VERSION 5.8 ;
BUSBITCHARS "[]" ;
DIVIDERCHAR "/" ;
UNITS
    DATABASE MICRONS 1000 ;
END UNITS

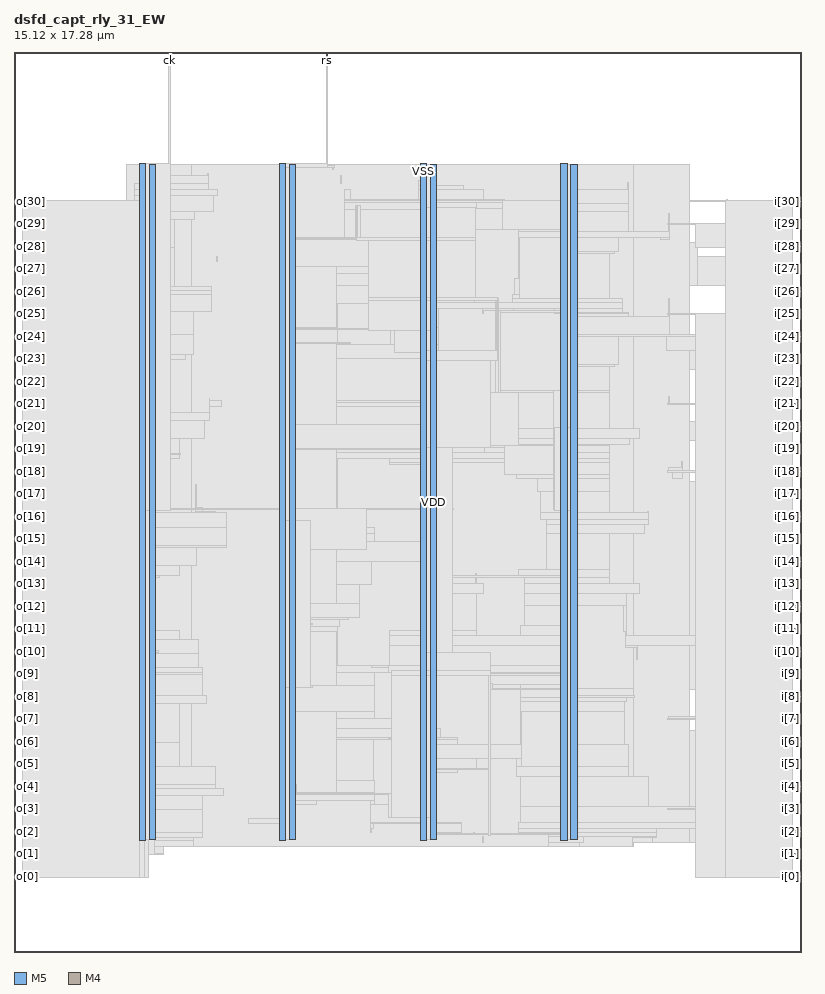
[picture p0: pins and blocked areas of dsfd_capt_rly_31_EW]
MACRO dsfd_capt_rly_31_EW
  FOREIGN dsfd_capt_rly_31_EW 0 0 ;
  CLASS BLOCK ;
  SIZE 15.12 BY 17.28 ;
  PIN ck
    DIRECTION INPUT ;
    USE SIGNAL ;
    PORT
      LAYER M5 ;
        RECT  2.976 17.088 3 17.28 ;
    END
  END ck
  PIN i[0]
    DIRECTION INPUT ;
    USE SIGNAL ;
    PORT
      LAYER M4 ;
        RECT  14.928 1.44 15.12 1.464 ;
    END
  END i[0]
  PIN i[10]
    DIRECTION INPUT ;
    USE SIGNAL ;
    PORT
      LAYER M4 ;
        RECT  14.928 5.76 15.12 5.784 ;
    END
  END i[10]
  PIN i[11]
    DIRECTION INPUT ;
    USE SIGNAL ;
    PORT
      LAYER M4 ;
        RECT  14.928 6.192 15.12 6.216 ;
    END
  END i[11]
  PIN i[12]
    DIRECTION INPUT ;
    USE SIGNAL ;
    PORT
      LAYER M4 ;
        RECT  14.928 6.624 15.12 6.648 ;
    END
  END i[12]
  PIN i[13]
    DIRECTION INPUT ;
    USE SIGNAL ;
    PORT
      LAYER M4 ;
        RECT  14.928 7.056 15.12 7.08 ;
    END
  END i[13]
  PIN i[14]
    DIRECTION INPUT ;
    USE SIGNAL ;
    PORT
      LAYER M4 ;
        RECT  14.928 7.488 15.12 7.512 ;
    END
  END i[14]
  PIN i[15]
    DIRECTION INPUT ;
    USE SIGNAL ;
    PORT
      LAYER M4 ;
        RECT  14.928 7.92 15.12 7.944 ;
    END
  END i[15]
  PIN i[16]
    DIRECTION INPUT ;
    USE SIGNAL ;
    PORT
      LAYER M4 ;
        RECT  14.928 8.352 15.12 8.376 ;
    END
  END i[16]
  PIN i[17]
    DIRECTION INPUT ;
    USE SIGNAL ;
    PORT
      LAYER M4 ;
        RECT  14.928 8.784 15.12 8.808 ;
    END
  END i[17]
  PIN i[18]
    DIRECTION INPUT ;
    USE SIGNAL ;
    PORT
      LAYER M4 ;
        RECT  14.928 9.216 15.12 9.24 ;
    END
  END i[18]
  PIN i[19]
    DIRECTION INPUT ;
    USE SIGNAL ;
    PORT
      LAYER M4 ;
        RECT  14.928 9.648 15.12 9.672 ;
    END
  END i[19]
  PIN i[1]
    DIRECTION INPUT ;
    USE SIGNAL ;
    PORT
      LAYER M4 ;
        RECT  14.928 1.872 15.12 1.896 ;
    END
  END i[1]
  PIN i[20]
    DIRECTION INPUT ;
    USE SIGNAL ;
    PORT
      LAYER M4 ;
        RECT  14.928 10.08 15.12 10.104 ;
    END
  END i[20]
  PIN i[21]
    DIRECTION INPUT ;
    USE SIGNAL ;
    PORT
      LAYER M4 ;
        RECT  14.928 10.512 15.12 10.536 ;
    END
  END i[21]
  PIN i[22]
    DIRECTION INPUT ;
    USE SIGNAL ;
    PORT
      LAYER M4 ;
        RECT  14.928 10.944 15.12 10.968 ;
    END
  END i[22]
  PIN i[23]
    DIRECTION INPUT ;
    USE SIGNAL ;
    PORT
      LAYER M4 ;
        RECT  14.928 11.376 15.12 11.4 ;
    END
  END i[23]
  PIN i[24]
    DIRECTION INPUT ;
    USE SIGNAL ;
    PORT
      LAYER M4 ;
        RECT  14.928 11.808 15.12 11.832 ;
    END
  END i[24]
  PIN i[25]
    DIRECTION INPUT ;
    USE SIGNAL ;
    PORT
      LAYER M4 ;
        RECT  14.928 12.24 15.12 12.264 ;
    END
  END i[25]
  PIN i[26]
    DIRECTION INPUT ;
    USE SIGNAL ;
    PORT
      LAYER M4 ;
        RECT  14.928 12.672 15.12 12.696 ;
    END
  END i[26]
  PIN i[27]
    DIRECTION INPUT ;
    USE SIGNAL ;
    PORT
      LAYER M4 ;
        RECT  14.928 13.104 15.12 13.128 ;
    END
  END i[27]
  PIN i[28]
    DIRECTION INPUT ;
    USE SIGNAL ;
    PORT
      LAYER M4 ;
        RECT  14.928 13.536 15.12 13.56 ;
    END
  END i[28]
  PIN i[29]
    DIRECTION INPUT ;
    USE SIGNAL ;
    PORT
      LAYER M4 ;
        RECT  14.928 13.968 15.12 13.992 ;
    END
  END i[29]
  PIN i[2]
    DIRECTION INPUT ;
    USE SIGNAL ;
    PORT
      LAYER M4 ;
        RECT  14.928 2.304 15.12 2.328 ;
    END
  END i[2]
  PIN i[30]
    DIRECTION INPUT ;
    USE SIGNAL ;
    PORT
      LAYER M4 ;
        RECT  14.928 14.4 15.12 14.424 ;
    END
  END i[30]
  PIN i[3]
    DIRECTION INPUT ;
    USE SIGNAL ;
    PORT
      LAYER M4 ;
        RECT  14.928 2.736 15.12 2.76 ;
    END
  END i[3]
  PIN i[4]
    DIRECTION INPUT ;
    USE SIGNAL ;
    PORT
      LAYER M4 ;
        RECT  14.928 3.168 15.12 3.192 ;
    END
  END i[4]
  PIN i[5]
    DIRECTION INPUT ;
    USE SIGNAL ;
    PORT
      LAYER M4 ;
        RECT  14.928 3.6 15.12 3.624 ;
    END
  END i[5]
  PIN i[6]
    DIRECTION INPUT ;
    USE SIGNAL ;
    PORT
      LAYER M4 ;
        RECT  14.928 4.032 15.12 4.056 ;
    END
  END i[6]
  PIN i[7]
    DIRECTION INPUT ;
    USE SIGNAL ;
    PORT
      LAYER M4 ;
        RECT  14.928 4.464 15.12 4.488 ;
    END
  END i[7]
  PIN i[8]
    DIRECTION INPUT ;
    USE SIGNAL ;
    PORT
      LAYER M4 ;
        RECT  14.928 4.896 15.12 4.92 ;
    END
  END i[8]
  PIN i[9]
    DIRECTION INPUT ;
    USE SIGNAL ;
    PORT
      LAYER M4 ;
        RECT  14.928 5.328 15.12 5.352 ;
    END
  END i[9]
  PIN o[0]
    DIRECTION OUTPUT ;
    USE SIGNAL ;
    PORT
      LAYER M4 ;
        RECT  0 1.44 0.192 1.464 ;
    END
  END o[0]
  PIN o[10]
    DIRECTION OUTPUT ;
    USE SIGNAL ;
    PORT
      LAYER M4 ;
        RECT  0 5.76 0.192 5.784 ;
    END
  END o[10]
  PIN o[11]
    DIRECTION OUTPUT ;
    USE SIGNAL ;
    PORT
      LAYER M4 ;
        RECT  0 6.192 0.192 6.216 ;
    END
  END o[11]
  PIN o[12]
    DIRECTION OUTPUT ;
    USE SIGNAL ;
    PORT
      LAYER M4 ;
        RECT  0 6.624 0.192 6.648 ;
    END
  END o[12]
  PIN o[13]
    DIRECTION OUTPUT ;
    USE SIGNAL ;
    PORT
      LAYER M4 ;
        RECT  0 7.056 0.192 7.08 ;
    END
  END o[13]
  PIN o[14]
    DIRECTION OUTPUT ;
    USE SIGNAL ;
    PORT
      LAYER M4 ;
        RECT  0 7.488 0.192 7.512 ;
    END
  END o[14]
  PIN o[15]
    DIRECTION OUTPUT ;
    USE SIGNAL ;
    PORT
      LAYER M4 ;
        RECT  0 7.92 0.192 7.944 ;
    END
  END o[15]
  PIN o[16]
    DIRECTION OUTPUT ;
    USE SIGNAL ;
    PORT
      LAYER M4 ;
        RECT  0 8.352 0.192 8.376 ;
    END
  END o[16]
  PIN o[17]
    DIRECTION OUTPUT ;
    USE SIGNAL ;
    PORT
      LAYER M4 ;
        RECT  0 8.784 0.192 8.808 ;
    END
  END o[17]
  PIN o[18]
    DIRECTION OUTPUT ;
    USE SIGNAL ;
    PORT
      LAYER M4 ;
        RECT  0 9.216 0.192 9.24 ;
    END
  END o[18]
  PIN o[19]
    DIRECTION OUTPUT ;
    USE SIGNAL ;
    PORT
      LAYER M4 ;
        RECT  0 9.648 0.192 9.672 ;
    END
  END o[19]
  PIN o[1]
    DIRECTION OUTPUT ;
    USE SIGNAL ;
    PORT
      LAYER M4 ;
        RECT  0 1.872 0.192 1.896 ;
    END
  END o[1]
  PIN o[20]
    DIRECTION OUTPUT ;
    USE SIGNAL ;
    PORT
      LAYER M4 ;
        RECT  0 10.08 0.192 10.104 ;
    END
  END o[20]
  PIN o[21]
    DIRECTION OUTPUT ;
    USE SIGNAL ;
    PORT
      LAYER M4 ;
        RECT  0 10.512 0.192 10.536 ;
    END
  END o[21]
  PIN o[22]
    DIRECTION OUTPUT ;
    USE SIGNAL ;
    PORT
      LAYER M4 ;
        RECT  0 10.944 0.192 10.968 ;
    END
  END o[22]
  PIN o[23]
    DIRECTION OUTPUT ;
    USE SIGNAL ;
    PORT
      LAYER M4 ;
        RECT  0 11.376 0.192 11.4 ;
    END
  END o[23]
  PIN o[24]
    DIRECTION OUTPUT ;
    USE SIGNAL ;
    PORT
      LAYER M4 ;
        RECT  0 11.808 0.192 11.832 ;
    END
  END o[24]
  PIN o[25]
    DIRECTION OUTPUT ;
    USE SIGNAL ;
    PORT
      LAYER M4 ;
        RECT  0 12.24 0.192 12.264 ;
    END
  END o[25]
  PIN o[26]
    DIRECTION OUTPUT ;
    USE SIGNAL ;
    PORT
      LAYER M4 ;
        RECT  0 12.672 0.192 12.696 ;
    END
  END o[26]
  PIN o[27]
    DIRECTION OUTPUT ;
    USE SIGNAL ;
    PORT
      LAYER M4 ;
        RECT  0 13.104 0.192 13.128 ;
    END
  END o[27]
  PIN o[28]
    DIRECTION OUTPUT ;
    USE SIGNAL ;
    PORT
      LAYER M4 ;
        RECT  0 13.536 0.192 13.56 ;
    END
  END o[28]
  PIN o[29]
    DIRECTION OUTPUT ;
    USE SIGNAL ;
    PORT
      LAYER M4 ;
        RECT  0 13.968 0.192 13.992 ;
    END
  END o[29]
  PIN o[2]
    DIRECTION OUTPUT ;
    USE SIGNAL ;
    PORT
      LAYER M4 ;
        RECT  0 2.304 0.192 2.328 ;
    END
  END o[2]
  PIN o[30]
    DIRECTION OUTPUT ;
    USE SIGNAL ;
    PORT
      LAYER M4 ;
        RECT  0 14.4 0.192 14.424 ;
    END
  END o[30]
  PIN o[3]
    DIRECTION OUTPUT ;
    USE SIGNAL ;
    PORT
      LAYER M4 ;
        RECT  0 2.736 0.192 2.76 ;
    END
  END o[3]
  PIN o[4]
    DIRECTION OUTPUT ;
    USE SIGNAL ;
    PORT
      LAYER M4 ;
        RECT  0 3.168 0.192 3.192 ;
    END
  END o[4]
  PIN o[5]
    DIRECTION OUTPUT ;
    USE SIGNAL ;
    PORT
      LAYER M4 ;
        RECT  0 3.6 0.192 3.624 ;
    END
  END o[5]
  PIN o[6]
    DIRECTION OUTPUT ;
    USE SIGNAL ;
    PORT
      LAYER M4 ;
        RECT  0 4.032 0.192 4.056 ;
    END
  END o[6]
  PIN o[7]
    DIRECTION OUTPUT ;
    USE SIGNAL ;
    PORT
      LAYER M4 ;
        RECT  0 4.464 0.192 4.488 ;
    END
  END o[7]
  PIN o[8]
    DIRECTION OUTPUT ;
    USE SIGNAL ;
    PORT
      LAYER M4 ;
        RECT  0 4.896 0.192 4.92 ;
    END
  END o[8]
  PIN o[9]
    DIRECTION OUTPUT ;
    USE SIGNAL ;
    PORT
      LAYER M4 ;
        RECT  0 5.328 0.192 5.352 ;
    END
  END o[9]
  PIN rs
    DIRECTION INPUT ;
    USE SIGNAL ;
    PORT
      LAYER M5 ;
        RECT  6 17.088 6.024 17.28 ;
    END
  END rs
  PIN VDD
    DIRECTION INOUT ;
    USE POWER ;
    PORT
      LAYER M5 ;
        RECT  10.692 2.151 10.812 15.129 ;
        RECT  7.992 2.151 8.112 15.129 ;
        RECT  5.292 2.151 5.412 15.129 ;
        RECT  2.592 2.151 2.712 15.129 ;
    END
  END VDD
  PIN VSS
    DIRECTION INOUT ;
    USE GROUND ;
    PORT
      LAYER M5 ;
        RECT  10.5 2.137 10.62 15.143 ;
        RECT  7.8 2.137 7.92 15.143 ;
        RECT  5.1 2.137 5.22 15.143 ;
        RECT  2.4 2.137 2.52 15.143 ;
    END
  END VSS
  OBS
    LAYER RVTN ;
     RECT  2.16 2.16 12.96 2.295 ;
     RECT  2.16 2.565 12.96 2.835 ;
     RECT  2.16 3.105 12.96 3.375 ;
     RECT  2.16 3.645 12.96 3.915 ;
     RECT  2.16 4.185 12.96 4.455 ;
     RECT  2.16 4.725 12.96 4.995 ;
     RECT  2.16 5.265 12.96 5.535 ;
     RECT  2.16 5.805 12.96 6.075 ;
     RECT  2.16 6.345 12.96 6.615 ;
     RECT  2.16 6.885 12.96 7.155 ;
     RECT  2.16 7.425 12.96 7.695 ;
     RECT  2.16 7.965 12.96 8.235 ;
     RECT  2.16 8.505 12.96 8.775 ;
     RECT  2.16 9.045 12.96 9.315 ;
     RECT  2.16 9.585 12.96 9.855 ;
     RECT  2.16 10.125 12.96 10.395 ;
     RECT  2.16 10.665 12.96 10.935 ;
     RECT  2.16 11.205 12.96 11.475 ;
     RECT  2.16 11.745 12.96 12.015 ;
     RECT  2.16 12.285 12.96 12.555 ;
     RECT  2.16 12.825 12.96 13.095 ;
     RECT  2.16 13.365 12.96 13.635 ;
     RECT  2.16 13.905 12.96 14.175 ;
     RECT  2.16 14.445 12.96 14.715 ;
     RECT  2.16 14.985 12.96 15.12 ;
    LAYER RVTP ;
     RECT  2.16 2.295 12.96 2.565 ;
     RECT  2.16 2.835 12.96 3.105 ;
     RECT  2.16 3.375 12.96 3.645 ;
     RECT  2.16 3.915 12.96 4.185 ;
     RECT  2.16 4.455 12.96 4.725 ;
     RECT  2.16 4.995 12.96 5.265 ;
     RECT  2.16 5.535 12.96 5.805 ;
     RECT  2.16 6.075 12.96 6.345 ;
     RECT  2.16 6.615 12.96 6.885 ;
     RECT  2.16 7.155 12.96 7.425 ;
     RECT  2.16 7.695 12.96 7.965 ;
     RECT  2.16 8.235 12.96 8.505 ;
     RECT  2.16 8.775 12.96 9.045 ;
     RECT  2.16 9.315 12.96 9.585 ;
     RECT  2.16 9.855 12.96 10.125 ;
     RECT  2.16 10.395 12.96 10.665 ;
     RECT  2.16 10.935 12.96 11.205 ;
     RECT  2.16 11.475 12.96 11.745 ;
     RECT  2.16 12.015 12.96 12.285 ;
     RECT  2.16 12.555 12.96 12.825 ;
     RECT  2.16 13.095 12.96 13.365 ;
     RECT  2.16 13.635 12.96 13.905 ;
     RECT  2.16 14.175 12.96 14.445 ;
     RECT  2.16 14.715 12.96 14.985 ;
    LAYER M1 ;
     RECT  2.16 2.151 12.96 15.129 ;
    LAYER M2 ;
     RECT  2.16 2.151 3.415 15.129 ;
     RECT  3.415 2.034 11.903 15.129 ;
     RECT  11.903 2.106 12.96 15.129 ;
     RECT  12.96 2.106 13.127 4.248 ;
     RECT  12.96 5.04 13.127 9.036 ;
     RECT  12.96 9.828 13.127 10.188 ;
     RECT  12.96 11.178 13.127 11.844 ;
     RECT  12.96 12.798 13.127 13.626 ;
     RECT  13.127 2.268 13.703 2.286 ;
     RECT  13.127 6.822 13.703 6.84 ;
     RECT  13.127 9.018 13.703 9.036 ;
     RECT  13.127 12.798 13.703 13.356 ;
     RECT  12.96 14.418 13.703 14.436 ;
     RECT  13.127 11.178 14.279 11.196 ;
     RECT  13.703 13.338 14.279 13.356 ;
    LAYER M3 ;
     RECT  2.556 1.435 2.574 1.867 ;
     RECT  13.104 1.435 13.122 1.867 ;
     RECT  2.556 1.867 2.862 2.029 ;
     RECT  10.26 2.029 10.854 2.101 ;
     RECT  11.88 2.029 11.898 2.101 ;
     RECT  2.556 2.029 3.438 2.143 ;
     RECT  2.415 2.143 3.438 2.191 ;
     RECT  11.88 2.101 12.258 2.191 ;
     RECT  9 2.101 9.018 2.219 ;
     RECT  10.26 2.101 10.926 2.227 ;
     RECT  11.88 2.191 12.33 2.227 ;
     RECT  8.82 2.251 8.838 2.291 ;
     RECT  13.104 1.867 13.698 2.291 ;
     RECT  2.415 2.191 3.618 2.299 ;
     RECT  7.815 2.143 7.905 2.299 ;
     RECT  10.26 2.227 12.33 2.299 ;
     RECT  6.84 2.299 6.858 2.371 ;
     RECT  9.684 2.299 12.33 2.371 ;
     RECT  13.104 2.291 13.122 2.371 ;
     RECT  5.115 2.143 5.205 2.413 ;
     RECT  5.115 2.413 5.397 2.461 ;
     RECT  6.84 2.371 6.894 2.461 ;
     RECT  7.815 2.299 8.586 2.461 ;
     RECT  6.84 2.461 8.586 2.489 ;
     RECT  9.684 2.371 13.122 2.489 ;
     RECT  4.5 2.461 5.397 2.561 ;
     RECT  2.304 2.299 3.618 2.731 ;
     RECT  9.72 2.489 13.122 2.795 ;
     RECT  6.84 2.489 8.097 2.831 ;
     RECT  5.115 2.561 5.397 2.839 ;
     RECT  5.115 2.839 5.814 2.911 ;
     RECT  6.84 2.831 6.93 2.911 ;
     RECT  2.268 2.731 3.618 3.001 ;
     RECT  5.115 2.911 6.93 3.065 ;
     RECT  2.268 3.001 4.014 3.137 ;
     RECT  2.268 3.137 3.87 3.209 ;
     RECT  5.115 3.065 5.418 3.209 ;
     RECT  6.192 3.065 6.93 3.299 ;
     RECT  9.72 2.795 12.186 3.371 ;
     RECT  9.72 3.371 11.79 3.379 ;
     RECT  7.815 2.831 8.097 3.451 ;
     RECT  7.815 3.451 8.514 3.499 ;
     RECT  2.415 3.209 3.87 3.569 ;
     RECT  9.648 3.379 11.79 3.569 ;
     RECT  7.815 3.499 8.874 3.721 ;
     RECT  9.648 3.569 9.738 3.721 ;
     RECT  7.815 3.721 9.738 3.983 ;
     RECT  10.515 3.569 11.79 3.983 ;
     RECT  2.415 3.569 3.186 4.027 ;
     RECT  6.192 3.299 6.894 4.075 ;
     RECT  7.815 3.983 8.514 4.075 ;
     RECT  6.192 4.075 8.514 4.109 ;
     RECT  6.192 4.109 8.19 4.289 ;
     RECT  13.104 2.795 13.122 4.459 ;
     RECT  6.192 4.289 8.097 4.487 ;
     RECT  12.564 4.459 13.122 4.523 ;
     RECT  5.115 3.209 5.397 4.621 ;
     RECT  6.192 4.487 6.93 4.621 ;
     RECT  9.72 3.983 9.738 4.621 ;
     RECT  10.515 3.983 11.718 4.621 ;
     RECT  2.304 4.027 3.186 4.765 ;
     RECT  9.72 4.621 11.718 4.801 ;
     RECT  9.72 4.801 11.754 4.891 ;
     RECT  2.304 4.765 3.69 4.919 ;
     RECT  9.72 4.891 11.898 5.063 ;
     RECT  5.115 4.621 6.93 5.117 ;
     RECT  9.72 5.063 10.797 5.131 ;
     RECT  9.144 5.131 10.797 5.305 ;
     RECT  2.304 4.919 3.618 5.323 ;
     RECT  7.815 4.487 8.097 5.341 ;
     RECT  8.82 5.305 10.797 5.341 ;
     RECT  2.268 5.323 3.618 5.369 ;
     RECT  6.192 5.117 6.93 5.371 ;
     RECT  7.815 5.341 10.797 5.371 ;
     RECT  2.376 5.369 3.618 5.459 ;
     RECT  6.192 5.371 10.797 5.501 ;
     RECT  2.376 5.459 3.546 5.729 ;
     RECT  11.952 5.611 11.97 5.845 ;
     RECT  7.2 5.501 10.797 5.881 ;
     RECT  11.736 5.845 11.97 5.881 ;
     RECT  13.104 4.523 13.122 5.881 ;
     RECT  2.412 5.729 3.546 5.999 ;
     RECT  7.2 5.881 10.818 6.071 ;
     RECT  11.736 5.881 13.122 6.071 ;
     RECT  5.115 5.117 5.397 6.151 ;
     RECT  6.192 5.501 6.21 6.151 ;
     RECT  11.736 6.071 11.754 6.151 ;
     RECT  2.412 5.999 3.186 6.179 ;
     RECT  7.2 6.071 8.874 6.179 ;
     RECT  5.115 6.151 6.21 6.241 ;
     RECT  9.72 6.071 10.818 6.269 ;
     RECT  5.115 6.241 6.246 6.385 ;
     RECT  5.115 6.385 6.426 6.421 ;
     RECT  13.104 6.071 13.122 6.619 ;
     RECT  9.792 6.269 10.818 6.655 ;
     RECT  11.7 6.151 11.754 6.655 ;
     RECT  5.115 6.421 6.642 6.683 ;
     RECT  13.104 6.619 13.698 6.845 ;
     RECT  7.815 6.179 8.874 6.889 ;
     RECT  9.792 6.655 11.754 6.889 ;
     RECT  2.412 6.179 2.697 7.051 ;
     RECT  6.192 6.683 6.642 7.051 ;
     RECT  7.815 6.889 9.018 7.079 ;
     RECT  9.792 6.889 12.006 7.079 ;
     RECT  2.304 7.051 2.697 7.195 ;
     RECT  9.792 7.079 11.43 7.195 ;
     RECT  2.304 7.195 2.79 7.231 ;
     RECT  8.856 7.079 8.874 7.259 ;
     RECT  9.684 7.195 11.43 7.349 ;
     RECT  2.304 7.231 3.186 7.429 ;
     RECT  6.192 7.051 6.858 7.501 ;
     RECT  7.815 7.079 8.097 7.501 ;
     RECT  2.304 7.429 3.51 7.771 ;
     RECT  2.304 7.771 4.086 7.799 ;
     RECT  6.192 7.501 8.097 7.889 ;
     RECT  5.115 6.683 5.397 8.041 ;
     RECT  6.192 7.889 6.93 8.041 ;
     RECT  10.224 7.349 11.43 8.041 ;
     RECT  2.376 7.799 4.086 8.159 ;
     RECT  5.115 8.041 6.93 8.159 ;
     RECT  10.224 8.041 12.114 8.203 ;
     RECT  5.115 8.159 6.462 8.303 ;
     RECT  10.224 8.203 12.186 8.311 ;
     RECT  2.412 8.159 4.086 8.429 ;
     RECT  10.116 8.311 12.186 8.429 ;
     RECT  3.492 8.429 3.87 8.465 ;
     RECT  12.168 8.429 12.186 8.465 ;
     RECT  7.815 7.889 8.097 8.491 ;
     RECT  13.104 6.845 13.122 8.501 ;
     RECT  3.492 8.465 3.618 8.537 ;
     RECT  7.815 8.491 8.406 8.537 ;
     RECT  10.116 8.429 11.43 8.851 ;
     RECT  3.492 8.537 3.51 8.969 ;
     RECT  13.68 8.779 13.698 9.041 ;
     RECT  10.044 8.851 11.43 9.085 ;
     RECT  9.648 9.085 11.43 9.163 ;
     RECT  2.412 8.429 2.697 9.211 ;
     RECT  12.636 9.085 12.834 9.211 ;
     RECT  12.564 9.211 12.834 9.311 ;
     RECT  7.815 8.537 8.097 9.319 ;
     RECT  7.815 9.319 8.19 9.355 ;
     RECT  7.2 9.355 8.19 9.391 ;
     RECT  9.432 9.163 11.43 9.391 ;
     RECT  12.816 9.311 12.834 9.419 ;
     RECT  2.304 9.211 2.697 9.481 ;
     RECT  6.192 8.303 6.21 9.481 ;
     RECT  7.2 9.391 11.43 9.481 ;
     RECT  6.192 9.481 11.43 9.581 ;
     RECT  5.115 8.303 5.397 9.643 ;
     RECT  6.192 9.581 8.097 9.643 ;
     RECT  0.216 9.547 0.234 9.677 ;
     RECT  9.036 9.581 11.43 9.725 ;
     RECT  9.684 9.725 11.43 9.751 ;
     RECT  2.304 9.481 3.186 9.859 ;
     RECT  9.684 9.751 11.826 9.859 ;
     RECT  9.684 9.859 12.006 10.049 ;
     RECT  5.115 9.643 8.097 10.121 ;
     RECT  13.104 9.643 13.122 10.193 ;
     RECT  2.304 9.859 3.654 10.201 ;
     RECT  2.304 10.201 3.762 10.355 ;
     RECT  3.744 10.355 3.762 10.471 ;
     RECT  6.192 10.121 8.097 10.471 ;
     RECT  6.192 10.471 8.478 10.555 ;
     RECT  3.744 10.471 3.978 10.589 ;
     RECT  6.192 10.555 8.874 10.595 ;
     RECT  2.304 10.355 2.79 10.625 ;
     RECT  3.744 10.589 3.762 10.625 ;
     RECT  12.564 10.507 12.582 10.661 ;
     RECT  9.684 10.049 11.43 10.741 ;
     RECT  9.432 10.741 11.43 10.781 ;
     RECT  14.256 10.939 14.274 11.201 ;
     RECT  10.515 10.781 11.43 11.245 ;
     RECT  10.515 11.245 11.538 11.281 ;
     RECT  2.304 10.625 2.697 11.371 ;
     RECT  6.192 10.595 8.514 11.399 ;
     RECT  9.288 11.365 9.306 11.405 ;
     RECT  2.304 11.371 3.294 11.479 ;
     RECT  9.144 11.509 9.162 11.549 ;
     RECT  13.104 11.371 13.122 11.551 ;
     RECT  6.192 11.399 8.154 11.669 ;
     RECT  5.115 10.121 5.397 11.677 ;
     RECT  6.192 11.669 6.462 11.677 ;
     RECT  5.115 11.677 6.462 11.705 ;
     RECT  10.515 11.281 11.61 11.821 ;
     RECT  12.528 11.551 13.122 11.821 ;
     RECT  2.304 11.479 3.438 11.849 ;
     RECT  10.515 11.821 13.122 11.849 ;
     RECT  5.115 11.705 6.21 11.981 ;
     RECT  7.236 11.669 8.154 11.981 ;
     RECT  10.515 11.849 12.582 12.209 ;
     RECT  10.515 12.209 11.79 12.253 ;
     RECT  10.368 12.253 11.79 12.281 ;
     RECT  2.415 11.849 3.438 12.289 ;
     RECT  9 12.253 9.018 12.325 ;
     RECT  7.776 11.981 8.154 12.361 ;
     RECT  9 12.325 9.594 12.361 ;
     RECT  10.368 12.281 11.682 12.361 ;
     RECT  6.192 11.981 6.21 12.451 ;
     RECT  7.776 12.361 11.682 12.479 ;
     RECT  9.576 12.479 11.682 12.551 ;
     RECT  12.564 12.209 12.582 12.551 ;
     RECT  7.776 12.479 8.838 12.557 ;
     RECT  9.576 12.551 9.702 12.623 ;
     RECT  2.415 12.289 3.798 12.631 ;
     RECT  2.304 12.631 3.798 12.701 ;
     RECT  2.412 12.701 3.798 12.785 ;
     RECT  6.192 12.451 6.858 12.793 ;
     RECT  7.776 12.557 8.514 12.793 ;
     RECT  13.68 12.667 13.698 12.821 ;
     RECT  9.612 12.623 9.702 12.929 ;
     RECT  6.192 12.793 8.514 13.019 ;
     RECT  5.115 11.981 5.397 13.171 ;
     RECT  6.192 13.019 8.154 13.171 ;
     RECT  3.888 13.261 3.906 13.361 ;
     RECT  14.256 13.099 14.274 13.361 ;
     RECT  10.515 12.551 11.43 13.405 ;
     RECT  10.515 13.405 11.538 13.441 ;
     RECT  2.412 12.785 3.078 13.531 ;
     RECT  13.104 13.531 13.122 13.631 ;
     RECT  5.115 13.171 8.154 13.709 ;
     RECT  9.684 12.929 9.702 13.711 ;
     RECT  10.515 13.441 11.61 13.711 ;
     RECT  12.42 13.675 12.582 13.711 ;
     RECT  9.684 13.711 12.582 13.829 ;
     RECT  2.304 13.531 3.078 14.071 ;
     RECT  12.564 13.829 12.582 14.171 ;
     RECT  2.304 14.071 3.474 14.215 ;
     RECT  9.684 13.829 11.79 14.215 ;
     RECT  6.336 13.709 8.154 14.251 ;
     RECT  9.648 14.215 11.79 14.369 ;
     RECT  6.336 14.251 8.874 14.395 ;
     RECT  9.648 14.369 9.702 14.395 ;
     RECT  6.336 14.395 9.702 14.429 ;
     RECT  6.336 14.429 9.414 14.441 ;
     RECT  13.68 14.395 13.698 14.441 ;
     RECT  2.304 14.215 3.834 14.521 ;
     RECT  2.304 14.521 3.906 14.639 ;
     RECT  6.336 14.441 6.462 14.639 ;
     RECT  7.776 14.441 9.018 14.639 ;
     RECT  10.515 14.369 11.79 14.639 ;
     RECT  7.776 14.639 8.622 14.711 ;
     RECT  2.304 14.639 3.726 14.747 ;
     RECT  11.772 14.639 11.79 14.783 ;
     RECT  7.776 14.711 8.097 14.819 ;
     RECT  5.115 13.709 5.397 14.867 ;
     RECT  7.815 14.819 8.097 14.867 ;
     RECT  10.515 14.639 10.797 14.867 ;
     RECT  2.415 14.747 3.726 14.909 ;
     RECT  6.264 14.755 6.282 14.909 ;
     RECT  3.708 14.909 3.726 14.945 ;
     RECT  6.12 15.025 6.138 15.101 ;
     RECT  2.415 14.909 2.505 15.137 ;
     RECT  5.115 14.867 5.205 15.137 ;
     RECT  7.815 14.867 7.905 15.137 ;
     RECT  10.515 14.867 10.605 15.137 ;
    LAYER M4 ;
     RECT  0.156 1.44 2.408 14.424 ;
     RECT  2.408 1.44 2.512 15.132 ;
     RECT  2.512 1.44 2.585 14.862 ;
     RECT  2.585 1.872 2.704 14.862 ;
     RECT  2.704 5.76 2.765 5.784 ;
     RECT  2.704 1.872 2.873 1.896 ;
     RECT  2.704 9.552 3.197 9.576 ;
     RECT  2.704 8.496 5.108 8.52 ;
     RECT  5.108 2.148 5.212 15.132 ;
     RECT  5.212 2.418 5.404 15.096 ;
     RECT  5.404 6.288 5.699 6.648 ;
     RECT  5.404 5.088 5.725 5.112 ;
     RECT  5.699 6.288 5.74 6.312 ;
     RECT  5.404 15.072 6.149 15.096 ;
     RECT  5.404 13.68 6.565 13.704 ;
     RECT  6.565 13.68 6.652 14.328 ;
     RECT  5.404 7.728 6.761 8.52 ;
     RECT  6.652 13.68 6.805 13.704 ;
     RECT  5.404 3.024 7.189 3.048 ;
     RECT  6.865 5.472 7.189 5.496 ;
     RECT  5.404 11.952 7.297 11.976 ;
     RECT  7.189 2.592 7.808 3.048 ;
     RECT  7.196 4.08 7.808 4.104 ;
     RECT  7.189 5.376 7.808 5.496 ;
     RECT  6.761 8.496 7.808 8.52 ;
     RECT  5.404 9.648 7.808 9.672 ;
     RECT  7.297 11.52 7.808 11.976 ;
     RECT  6.805 13.056 7.808 13.704 ;
     RECT  7.808 2.148 7.912 15.132 ;
     RECT  7.912 2.256 8.104 14.862 ;
     RECT  8.104 8.496 8.435 8.52 ;
     RECT  8.104 5.328 9.109 5.736 ;
     RECT  8.104 3.504 9.155 3.528 ;
     RECT  9.109 5.04 9.155 5.736 ;
     RECT  8.104 9.696 9.155 11.544 ;
     RECT  9.155 5.04 9.196 5.16 ;
     RECT  9.155 10.752 9.253 11.544 ;
     RECT  8.104 12.528 9.253 12.552 ;
     RECT  9.253 10.752 9.299 12.552 ;
     RECT  9.299 10.752 9.34 12.312 ;
     RECT  8.104 13.872 9.385 14.28 ;
     RECT  9.155 9.696 9.421 9.72 ;
     RECT  9.421 9.168 10.357 9.72 ;
     RECT  9.34 10.752 10.357 10.776 ;
     RECT  8.104 2.256 10.508 2.28 ;
     RECT  9.196 5.04 10.508 5.064 ;
     RECT  8.104 7.2 10.508 7.224 ;
     RECT  10.357 8.496 10.508 10.776 ;
     RECT  9.34 12.288 10.508 12.312 ;
     RECT  9.385 13.872 10.508 14.424 ;
     RECT  10.508 2.148 10.612 15.132 ;
     RECT  10.612 2.418 10.804 14.862 ;
     RECT  10.804 4.896 11.909 4.92 ;
     RECT  12.553 2.736 13.093 2.76 ;
     RECT  12.553 4.464 13.093 4.488 ;
     RECT  12.553 9.216 13.093 9.24 ;
     RECT  12.553 10.512 13.093 10.536 ;
     RECT  12.553 12.24 13.093 12.264 ;
     RECT  12.553 13.968 13.093 13.992 ;
     RECT  13.093 1.44 13.669 12.264 ;
     RECT  13.093 13.536 13.669 13.992 ;
     RECT  13.669 1.44 14.94 14.424 ;
    LAYER M5 ;
     RECT  2.4 2.137 2.52 2.151 ;
     RECT  5.1 2.137 5.22 2.151 ;
     RECT  7.8 2.137 7.92 2.151 ;
     RECT  10.5 2.137 10.62 2.151 ;
     RECT  7.8 2.151 8.112 2.581 ;
     RECT  5.1 2.151 5.412 5.077 ;
     RECT  7.248 2.581 8.112 5.317 ;
     RECT  9.12 2.245 9.144 5.317 ;
     RECT  7.248 5.317 9.144 5.411 ;
     RECT  7.8 5.411 9.144 5.747 ;
     RECT  5.1 5.077 5.688 8.291 ;
     RECT  2.4 2.151 2.712 8.485 ;
     RECT  10.5 2.151 10.812 8.485 ;
     RECT  7.8 5.747 8.424 9.685 ;
     RECT  10.368 8.485 10.812 10.067 ;
     RECT  7.8 9.685 9.144 11.365 ;
     RECT  7.8 11.365 9.288 11.555 ;
     RECT  7.8 11.555 8.112 11.941 ;
     RECT  6.816 11.941 8.112 12.517 ;
     RECT  9.264 11.555 9.288 12.517 ;
     RECT  6.816 12.517 9.288 12.563 ;
     RECT  6.816 12.563 8.856 13.669 ;
     RECT  6.576 13.669 8.856 13.715 ;
     RECT  7.8 13.715 8.856 14.291 ;
     RECT  6.576 13.715 6.6 14.339 ;
     RECT  5.1 8.291 5.412 15.061 ;
     RECT  7.8 14.291 8.112 15.129 ;
     RECT  10.5 10.067 10.812 15.129 ;
     RECT  2.4 8.485 3 15.143 ;
     RECT  5.1 15.061 6.024 15.143 ;
     RECT  7.8 15.129 7.92 15.143 ;
     RECT  10.5 15.129 10.62 15.143 ;
     RECT  2.976 15.143 3 17.104 ;
     RECT  6 15.143 6.024 17.104 ;
  END
END dsfd_capt_rly_31_EW
END LIBRARY
